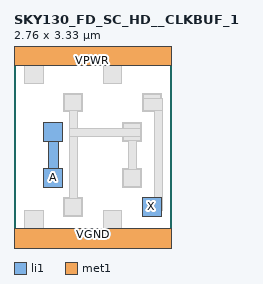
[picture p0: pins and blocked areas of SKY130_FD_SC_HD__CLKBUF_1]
MACRO SKY130_FD_SC_HD__CLKBUF_1
 CLASS CORE ;
 FOREIGN SKY130_FD_SC_HD__CLKBUF_1 0 0 ;
 SIZE 2.7600000000000002 BY 3.33 ;
 ORIGIN 0 0 ;
 SYMMETRY X Y R90 ;
 SITE unit ;
  PIN VPWR
   DIRECTION INOUT ;
   USE POWER ;
   SHAPE ABUTMENT ;
    PORT
     CLASS CORE ;
       LAYER li1 ;
        RECT 0.00000000 3.09000000 2.76000000 3.57000000 ;
       LAYER met1 ;
        RECT 0.00000000 3.09000000 2.76000000 3.57000000 ;
    END
  END VPWR

  PIN VGND
   DIRECTION INOUT ;
   USE POWER ;
   SHAPE ABUTMENT ;
    PORT
     CLASS CORE ;
       LAYER li1 ;
        RECT 0.00000000 -0.24000000 2.76000000 0.24000000 ;
       LAYER met1 ;
        RECT 0.00000000 -0.24000000 2.76000000 0.24000000 ;
    END
  END VGND

  PIN X
   DIRECTION INOUT ;
   USE SIGNAL ;
   SHAPE ABUTMENT ;
    PORT
     CLASS CORE ;
       LAYER li1 ;
        RECT 2.25000000 0.45000000 2.58000000 0.78000000 ;
    END
  END X

  PIN A
   DIRECTION INOUT ;
   USE SIGNAL ;
   SHAPE ABUTMENT ;
    PORT
     CLASS CORE ;
       LAYER li1 ;
        RECT 0.52500000 0.96000000 0.85500000 1.29000000 ;
        RECT 0.60500000 1.29000000 0.77500000 1.76000000 ;
        RECT 0.52500000 1.76000000 0.85500000 2.09000000 ;
    END
  END A

 OBS
    LAYER polycont ;
     RECT 0.60500000 1.04000000 0.77500000 1.21000000 ;
     RECT 1.98500000 1.04000000 2.15500000 1.21000000 ;
     RECT 0.60500000 1.84000000 0.77500000 2.01000000 ;
     RECT 1.98500000 1.84000000 2.15500000 2.01000000 ;

    LAYER pdiffc ;
     RECT 0.95000000 2.36000000 1.12000000 2.53000000 ;
     RECT 2.33000000 2.36000000 2.50000000 2.53000000 ;
     RECT 0.26000000 2.86000000 0.43000000 3.03000000 ;
     RECT 1.64000000 2.86000000 1.81000000 3.03000000 ;

    LAYER ndiffc ;
     RECT 0.26000000 0.30000000 0.43000000 0.47000000 ;
     RECT 1.64000000 0.30000000 1.81000000 0.47000000 ;
     RECT 0.95000000 0.53000000 1.12000000 0.70000000 ;
     RECT 2.33000000 0.53000000 2.50000000 0.70000000 ;

    LAYER li1 ;
     RECT 0.00000000 -0.24000000 2.76000000 0.24000000 ;
     RECT 0.18000000 0.24000000 0.51000000 0.55000000 ;
     RECT 1.56000000 0.24000000 1.89000000 0.55000000 ;
     RECT 0.87000000 0.45000000 1.20000000 0.78000000 ;
     RECT 2.25000000 0.45000000 2.58000000 0.78000000 ;
     RECT 1.90500000 0.96000000 2.23500000 1.29000000 ;
     RECT 0.52500000 0.96000000 0.85500000 1.29000000 ;
     RECT 0.60500000 1.29000000 0.77500000 1.76000000 ;
     RECT 0.52500000 1.76000000 0.85500000 2.09000000 ;
     RECT 1.90500000 1.76000000 2.23500000 2.09000000 ;
     RECT 0.87000000 2.28000000 1.20000000 2.61000000 ;
     RECT 2.25000000 2.28000000 2.58000000 2.61000000 ;
     RECT 0.18000000 2.78000000 0.51000000 3.09000000 ;
     RECT 1.56000000 2.78000000 1.89000000 3.09000000 ;
     RECT 0.00000000 3.09000000 2.76000000 3.57000000 ;

    LAYER viali ;
     RECT 0.26000000 -0.08500000 0.43000000 0.08500000 ;
     RECT 0.95000000 0.53000000 1.12000000 0.70000000 ;
     RECT 2.33000000 0.53000000 2.50000000 0.70000000 ;
     RECT 1.98500000 1.04000000 2.15500000 1.21000000 ;
     RECT 1.98500000 1.84000000 2.15500000 2.01000000 ;
     RECT 0.95000000 2.36000000 1.12000000 2.53000000 ;
     RECT 2.33000000 2.36000000 2.50000000 2.53000000 ;
     RECT 0.26000000 3.24500000 0.43000000 3.41500000 ;

    LAYER met1 ;
     RECT 0.00000000 -0.24000000 2.76000000 0.24000000 ;
     RECT 0.89000000 0.47000000 1.18000000 0.76000000 ;
     RECT 1.92500000 0.98000000 2.21500000 1.27000000 ;
     RECT 2.00000000 1.27000000 2.14000000 1.78000000 ;
     RECT 0.96500000 0.76000000 1.10500000 1.85500000 ;
     RECT 1.92500000 1.78000000 2.21500000 1.85500000 ;
     RECT 0.96500000 1.85500000 2.21500000 1.99500000 ;
     RECT 1.92500000 1.99500000 2.21500000 2.07000000 ;
     RECT 0.96500000 1.99500000 1.10500000 2.30000000 ;
     RECT 0.89000000 2.30000000 1.18000000 2.59000000 ;
     RECT 2.27000000 0.47000000 2.56000000 0.54500000 ;
     RECT 2.27000000 0.54500000 2.60000000 0.76000000 ;
     RECT 2.46000000 0.76000000 2.60000000 2.30000000 ;
     RECT 2.27000000 2.30000000 2.60000000 2.51500000 ;
     RECT 2.27000000 2.51500000 2.56000000 2.59000000 ;
     RECT 0.00000000 3.09000000 2.76000000 3.57000000 ;

    LAYER via ;


    LAYER met2 ;


    LAYER via2 ;


    LAYER met3 ;


 END
END SKY130_FD_SC_HD__CLKBUF_1
